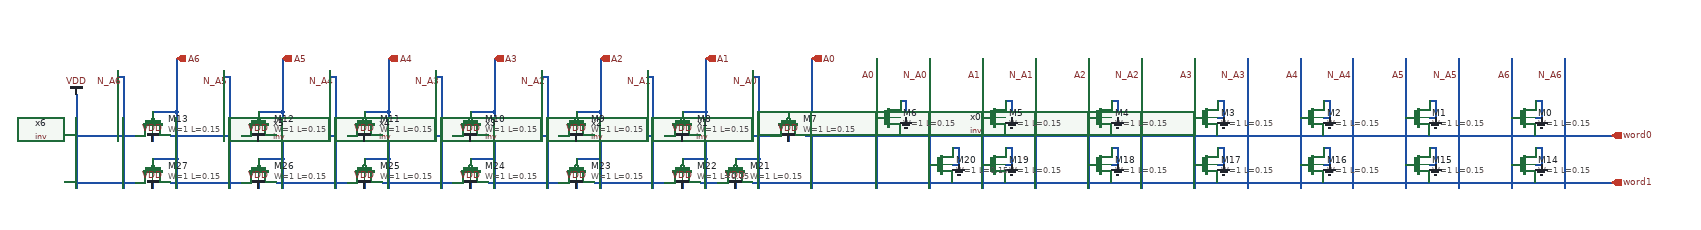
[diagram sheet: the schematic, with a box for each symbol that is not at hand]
v {xschem version=3.4.6 file_version=1.2}
G {}
K {}
V {}
S {}
E {}
N 1450 -60 1450 0 { }
N 1360 -60 1360 0 { }
N 1630 -60 1630 0 { }
N 1540 -60 1540 0 { }
N 1810 -60 1810 0 { }
N 1720 -60 1720 0 { }
N 1990 -60 1990 0 { }
N 1900 -60 1900 0 { }
N 2170 -60 2170 0 { }
N 2080 -60 2080 0 { }
N 2350 -60 2350 0 { }
N 2260 -60 2260 0 { }
N 2530 -60 2530 0 { }
N 2440 -60 2440 0 { }
N 1250 -60 1250 0 {lab=A0}
N 1150 -40 1150 -30 {lab=N_A0}
N 1150 -30 1160 -30 {lab=N_A0}
N 1160 -30 1160 0 {lab=N_A0}
N 1070 -60 1070 0 {lab=A1}
N 970 -40 970 -30 {lab=N_A1}
N 970 -30 980 -30 {lab=N_A1}
N 980 -30 980 0 {lab=N_A1}
N 890 -60 890 0 {lab=A2}
N 790 -40 790 -30 {lab=N_A2}
N 790 -30 800 -30 {lab=N_A2}
N 800 -30 800 0 {lab=N_A2}
N 710 -60 710 0 {lab=A3}
N 610 -40 610 -30 {lab=N_A3}
N 610 -30 620 -30 {lab=N_A3}
N 620 -30 620 0 {lab=N_A3}
N 530 -60 530 0 {lab=A4}
N 430 -40 430 -30 {lab=N_A4}
N 430 -30 440 -30 {lab=N_A4}
N 440 -30 440 0 {lab=N_A4}
N 350 -60 350 0 {lab=A5}
N 250 -40 250 -30 {lab=N_A5}
N 250 -30 260 -30 {lab=N_A5}
N 260 -30 260 0 {lab=N_A5}
N 170 -60 170 0 {lab=A6}
N 70 -40 70 -30 {lab=N_A6}
N 70 -30 80 -30 {lab=N_A6}
N 80 -30 80 0 {lab=N_A6}
N 2530 0 2530 80 {lab=N_A6}
N 2520 70 2610 70 {lab=word0}
N 2480 40 2490 40 {lab=GND}
N 2490 10 2490 40 {lab=GND}
N 2480 10 2490 10 {lab=GND}
N 2440 0 2440 40 {lab=A6}
N 2440 40 2440 80 {lab=A6}
N 2430 70 2480 70 {lab=word0}
N 2480 70 2520 70 {lab=word0}
N 2350 0 2350 80 {lab=N_A5}
N 2340 70 2430 70 {lab=word0}
N 2300 40 2310 40 {lab=GND}
N 2310 10 2310 40 {lab=GND}
N 2300 10 2310 10 {lab=GND}
N 2260 0 2260 40 {lab=A5}
N 2260 40 2260 80 {lab=A5}
N 2250 70 2300 70 {lab=word0}
N 2300 70 2340 70 {lab=word0}
N 2170 0 2170 80 {lab=N_A4}
N 2160 70 2250 70 {lab=word0}
N 2120 40 2130 40 {lab=GND}
N 2130 10 2130 40 {lab=GND}
N 2120 10 2130 10 {lab=GND}
N 2080 0 2080 40 {lab=A4}
N 2080 40 2080 80 {lab=A4}
N 2070 70 2120 70 {lab=word0}
N 2120 70 2160 70 {lab=word0}
N 1990 0 1990 80 {lab=N_A3}
N 1980 70 2070 70 {lab=word0}
N 1940 40 1950 40 {lab=GND}
N 1950 10 1950 40 {lab=GND}
N 1940 10 1950 10 {lab=GND}
N 1900 0 1900 40 {lab=A3}
N 1900 40 1900 80 {lab=A3}
N 1890 70 1940 70 {lab=word0}
N 1940 70 1980 70 {lab=word0}
N 1810 0 1810 80 {lab=N_A2}
N 1800 70 1890 70 {lab=word0}
N 1760 40 1770 40 {lab=GND}
N 1770 10 1770 40 {lab=GND}
N 1760 10 1770 10 {lab=GND}
N 1720 0 1720 40 {lab=A2}
N 1720 40 1720 80 {lab=A2}
N 1710 70 1760 70 {lab=word0}
N 1760 70 1800 70 {lab=word0}
N 1630 0 1630 80 {lab=N_A1}
N 1620 70 1710 70 {lab=word0}
N 1580 40 1590 40 {lab=GND}
N 1590 10 1590 40 {lab=GND}
N 1580 10 1590 10 {lab=GND}
N 1540 0 1540 40 {lab=A1}
N 1540 40 1540 80 {lab=A1}
N 1530 70 1580 70 {lab=word0}
N 1580 70 1620 70 {lab=word0}
N 1450 0 1450 80 {lab=N_A0}
N 1440 70 1530 70 {lab=word0}
N 1400 40 1410 40 {lab=GND}
N 1410 10 1410 40 {lab=GND}
N 1400 10 1410 10 {lab=GND}
N 1360 0 1360 40 {lab=A0}
N 1360 40 1360 80 {lab=A0}
N 1350 70 1400 70 {lab=word0}
N 1400 70 1440 70 {lab=word0}
N 1260 70 1350 70 { }
N 1210 30 1250 30 {lab=A7}
N 1210 70 1210 80 {lab=VDD}
N 1240 70 1260 70 {lab=word0}
N 1170 70 1180 70 {lab=#net015}
N 1250 0 1250 30 {lab=A7}
N 1250 30 1250 80 {lab=A7}
N 1160 0 1160 80 {lab=N_A8}
N 1080 70 1170 70 {lab=#net015}
N 1030 30 1070 30 {lab=A8}
N 1030 70 1030 80 {lab=VDD}
N 1060 70 1080 70 {lab=#net015}
N 990 70 1000 70 {lab=#net017}
N 1070 0 1070 30 {lab=A8}
N 1070 30 1070 80 {lab=A8}
N 980 0 980 80 {lab=N_A9}
N 900 70 990 70 {lab=#net017}
N 850 30 890 30 {lab=A9}
N 850 70 850 80 {lab=VDD}
N 880 70 900 70 {lab=#net017}
N 810 70 820 70 {lab=#net019}
N 890 0 890 30 {lab=A9}
N 890 30 890 80 {lab=A9}
N 800 0 800 80 {lab=N_A10}
N 720 70 810 70 {lab=#net019}
N 670 30 710 30 {lab=A10}
N 670 70 670 80 {lab=VDD}
N 700 70 720 70 {lab=#net019}
N 630 70 640 70 {lab=#net021}
N 710 0 710 30 {lab=A10}
N 710 30 710 80 {lab=A10}
N 620 0 620 80 {lab=N_A11}
N 540 70 630 70 {lab=#net021}
N 490 30 530 30 {lab=A11}
N 490 70 490 80 {lab=VDD}
N 520 70 540 70 {lab=#net021}
N 450 70 460 70 {lab=#net023}
N 530 0 530 30 {lab=A11}
N 530 30 530 80 {lab=A11}
N 440 0 440 80 {lab=N_A12}
N 360 70 450 70 {lab=#net023}
N 310 30 350 30 {lab=A12}
N 310 70 310 80 {lab=VDD}
N 340 70 360 70 {lab=#net023}
N 270 70 280 70 {lab=#net025}
N 350 0 350 30 {lab=A12}
N 350 30 350 80 {lab=A12}
N 260 0 260 80 {lab=N_A13}
N 180 70 270 70 {lab=#net025}
N 130 30 170 30 {lab=A13}
N 130 70 130 80 {lab=VDD}
N 160 70 180 70 {lab=#net025}
N 90 70 100 70 {lab=#net027}
N 170 0 170 30 {lab=A13}
N 170 30 170 80 {lab=A13}
N 80 0 80 80 {lab=N_A14}
N 0 70 90 70 {lab=#net027}
N 0 0 0 80 { }
N 2530 80 2530 160 {lab=N_A6}
N 2520 150 2610 150 {lab=word1}
N 2480 120 2490 120 {lab=GND}
N 2490 90 2490 120 {lab=GND}
N 2480 90 2490 90 {lab=GND}
N 2440 80 2440 120 {lab=A6}
N 2440 120 2440 160 {lab=A6}
N 2430 150 2480 150 {lab=word1}
N 2480 150 2520 150 {lab=word1}
N 2350 80 2350 160 {lab=N_A5}
N 2340 150 2430 150 {lab=word1}
N 2300 120 2310 120 {lab=GND}
N 2310 90 2310 120 {lab=GND}
N 2300 90 2310 90 {lab=GND}
N 2260 80 2260 120 {lab=A5}
N 2260 120 2260 160 {lab=A5}
N 2250 150 2300 150 {lab=word1}
N 2300 150 2340 150 {lab=word1}
N 2170 80 2170 160 {lab=N_A4}
N 2160 150 2250 150 {lab=word1}
N 2120 120 2130 120 {lab=GND}
N 2130 90 2130 120 {lab=GND}
N 2120 90 2130 90 {lab=GND}
N 2080 80 2080 120 {lab=A4}
N 2080 120 2080 160 {lab=A4}
N 2070 150 2120 150 {lab=word1}
N 2120 150 2160 150 {lab=word1}
N 1990 80 1990 160 {lab=N_A3}
N 1980 150 2070 150 {lab=word1}
N 1940 120 1950 120 {lab=GND}
N 1950 90 1950 120 {lab=GND}
N 1940 90 1950 90 {lab=GND}
N 1900 80 1900 120 {lab=A3}
N 1900 120 1900 160 {lab=A3}
N 1890 150 1940 150 {lab=word1}
N 1940 150 1980 150 {lab=word1}
N 1810 80 1810 160 {lab=N_A2}
N 1800 150 1890 150 {lab=word1}
N 1760 120 1770 120 {lab=GND}
N 1770 90 1770 120 {lab=GND}
N 1760 90 1770 90 {lab=GND}
N 1720 80 1720 120 {lab=A2}
N 1720 120 1720 160 {lab=A2}
N 1710 150 1760 150 {lab=word1}
N 1760 150 1800 150 {lab=word1}
N 1630 80 1630 160 {lab=N_A1}
N 1620 150 1710 150 {lab=word1}
N 1580 120 1590 120 {lab=GND}
N 1590 90 1590 120 {lab=GND}
N 1580 90 1590 90 {lab=GND}
N 1540 80 1540 120 {lab=A1}
N 1540 120 1540 160 {lab=A1}
N 1530 150 1580 150 {lab=word1}
N 1580 150 1620 150 {lab=word1}
N 1490 120 1500 120 {lab=GND}
N 1500 90 1500 120 {lab=GND}
N 1490 90 1500 90 {lab=GND}
N 1450 80 1450 120 {lab=N_A0}
N 1450 120 1450 160 {lab=N_A0}
N 1440 150 1490 150 {lab=word1}
N 1490 150 1530 150 {lab=word1}
N 1360 80 1360 160 {lab=A0}
N 1350 150 1440 150 {lab=word1}
N 1260 150 1350 150 { }
N 1250 80 1250 160 {lab=A7}
N 1170 150 1260 150 {lab=word1}
N 1120 110 1160 110 {lab=N_A8}
N 1120 150 1120 160 {lab=VDD}
N 1150 150 1170 150 {lab=word1}
N 1080 150 1090 150 {lab=#net115}
N 1160 80 1160 110 {lab=N_A8}
N 1160 110 1160 160 {lab=N_A8}
N 1030 110 1070 110 {lab=A8}
N 1030 150 1030 160 {lab=VDD}
N 1060 150 1080 150 {lab=#net115}
N 990 150 1000 150 {lab=#net117}
N 1070 80 1070 110 {lab=A8}
N 1070 110 1070 160 {lab=A8}
N 980 80 980 160 {lab=N_A9}
N 900 150 990 150 {lab=#net117}
N 850 110 890 110 {lab=A9}
N 850 150 850 160 {lab=VDD}
N 880 150 900 150 {lab=#net117}
N 810 150 820 150 {lab=#net119}
N 890 80 890 110 {lab=A9}
N 890 110 890 160 {lab=A9}
N 800 80 800 160 {lab=N_A10}
N 720 150 810 150 {lab=#net119}
N 670 110 710 110 {lab=A10}
N 670 150 670 160 {lab=VDD}
N 700 150 720 150 {lab=#net119}
N 630 150 640 150 {lab=#net121}
N 710 80 710 110 {lab=A10}
N 710 110 710 160 {lab=A10}
N 620 80 620 160 {lab=N_A11}
N 540 150 630 150 {lab=#net121}
N 490 110 530 110 {lab=A11}
N 490 150 490 160 {lab=VDD}
N 520 150 540 150 {lab=#net121}
N 450 150 460 150 {lab=#net123}
N 530 80 530 110 {lab=A11}
N 530 110 530 160 {lab=A11}
N 440 80 440 160 {lab=N_A12}
N 360 150 450 150 {lab=#net123}
N 310 110 350 110 {lab=A12}
N 310 150 310 160 {lab=VDD}
N 340 150 360 150 {lab=#net123}
N 270 150 280 150 {lab=#net125}
N 350 80 350 110 {lab=A12}
N 350 110 350 160 {lab=A12}
N 260 80 260 160 {lab=N_A13}
N 180 150 270 150 {lab=#net125}
N 130 110 170 110 {lab=A13}
N 130 150 130 160 {lab=VDD}
N 160 150 180 150 {lab=#net125}
N 90 150 100 150 {lab=#net127}
N 170 80 170 110 {lab=A13}
N 170 110 170 160 {lab=A13}
N 80 80 80 160 {lab=N_A14}
N 0 150 90 150 {lab=#net127}
N 0 80 0 160 { }
C {devices/vdd.sym} 0 0 0 0 {lab=VDD}
C {devices/lab_wire.sym} 1450 -30 0 0 {name=p0 lab=N_A0}
C {devices/lab_wire.sym} 1360 -30 0 0 {name=p1 lab=A0}
C {devices/lab_wire.sym} 1630 -30 0 0 {name=p2 lab=N_A1}
C {devices/lab_wire.sym} 1540 -30 0 0 {name=p3 lab=A1}
C {devices/lab_wire.sym} 1810 -30 0 0 {name=p4 lab=N_A2}
C {devices/lab_wire.sym} 1720 -30 0 0 {name=p5 lab=A2}
C {devices/lab_wire.sym} 1990 -30 0 0 {name=p6 lab=N_A3}
C {devices/lab_wire.sym} 1900 -30 0 0 {name=p7 lab=A3}
C {devices/lab_wire.sym} 2170 -30 0 0 {name=p8 lab=N_A4}
C {devices/lab_wire.sym} 2080 -30 0 0 {name=p9 lab=A4}
C {devices/lab_wire.sym} 2350 -30 0 0 {name=p10 lab=N_A5}
C {devices/lab_wire.sym} 2260 -30 0 0 {name=p11 lab=A5}
C {devices/lab_wire.sym} 2530 -30 0 0 {name=p12 lab=N_A6}
C {devices/lab_wire.sym} 2440 -30 0 0 {name=p13 lab=A6}
C {lab1/inv.sym} 1250 -90 2 0 {name=x0}
C {devices/ipin.sym} 1250 -60 3 1 {name=p14 lab=A0}
C {devices/lab_wire.sym} 1160 -20 0 0 {name=p15 sig_type=std_logic lab=N_A0}
C {lab1/inv.sym} 1070 -90 2 0 {name=x1}
C {devices/ipin.sym} 1070 -60 3 1 {name=p16 lab=A1}
C {devices/lab_wire.sym} 980 -20 0 0 {name=p17 sig_type=std_logic lab=N_A1}
C {lab1/inv.sym} 890 -90 2 0 {name=x2}
C {devices/ipin.sym} 890 -60 3 1 {name=p18 lab=A2}
C {devices/lab_wire.sym} 800 -20 0 0 {name=p19 sig_type=std_logic lab=N_A2}
C {lab1/inv.sym} 710 -90 2 0 {name=x3}
C {devices/ipin.sym} 710 -60 3 1 {name=p20 lab=A3}
C {devices/lab_wire.sym} 620 -20 0 0 {name=p21 sig_type=std_logic lab=N_A3}
C {lab1/inv.sym} 530 -90 2 0 {name=x4}
C {devices/ipin.sym} 530 -60 3 1 {name=p22 lab=A4}
C {devices/lab_wire.sym} 440 -20 0 0 {name=p23 sig_type=std_logic lab=N_A4}
C {lab1/inv.sym} 350 -90 2 0 {name=x5}
C {devices/ipin.sym} 350 -60 3 1 {name=p24 lab=A5}
C {devices/lab_wire.sym} 260 -20 0 0 {name=p25 sig_type=std_logic lab=N_A5}
C {lab1/inv.sym} 170 -90 2 0 {name=x6}
C {devices/ipin.sym} 170 -60 3 1 {name=p26 lab=A6}
C {devices/lab_wire.sym} 80 -20 0 0 {name=p27 sig_type=std_logic lab=N_A6}
C {devices/opin.sym} 2610 70 0 0 {name=p28 lab=word0}
C {sky130_fd_pr/nfet_01v8.sym} 2460 40 2 1 {name=M0
L=0.15
W=1
nf=1 
mult=1
ad="'int((nf+1)/2) * W/nf * 0.29'" 
pd="'2*int((nf+1)/2) * (W/nf + 0.29)'"
as="'int((nf+2)/2) * W/nf * 0.29'" 
ps="'2*int((nf+2)/2) * (W/nf + 0.29)'"
nrd="'0.29 / W'" nrs="'0.29 / W'"
sa=0 sb=0 sd=0
model=nfet_01v8
spiceprefix=X
}
C {devices/gnd.sym} 2490 40 3 0 {name=l0 lab=GND}
C {sky130_fd_pr/nfet_01v8.sym} 2280 40 2 1 {name=M1
L=0.15
W=1
nf=1 
mult=1
ad="'int((nf+1)/2) * W/nf * 0.29'" 
pd="'2*int((nf+1)/2) * (W/nf + 0.29)'"
as="'int((nf+2)/2) * W/nf * 0.29'" 
ps="'2*int((nf+2)/2) * (W/nf + 0.29)'"
nrd="'0.29 / W'" nrs="'0.29 / W'"
sa=0 sb=0 sd=0
model=nfet_01v8
spiceprefix=X
}
C {devices/gnd.sym} 2310 40 3 0 {name=l1 lab=GND}
C {sky130_fd_pr/nfet_01v8.sym} 2100 40 2 1 {name=M2
L=0.15
W=1
nf=1 
mult=1
ad="'int((nf+1)/2) * W/nf * 0.29'" 
pd="'2*int((nf+1)/2) * (W/nf + 0.29)'"
as="'int((nf+2)/2) * W/nf * 0.29'" 
ps="'2*int((nf+2)/2) * (W/nf + 0.29)'"
nrd="'0.29 / W'" nrs="'0.29 / W'"
sa=0 sb=0 sd=0
model=nfet_01v8
spiceprefix=X
}
C {devices/gnd.sym} 2130 40 3 0 {name=l2 lab=GND}
C {sky130_fd_pr/nfet_01v8.sym} 1920 40 2 1 {name=M3
L=0.15
W=1
nf=1 
mult=1
ad="'int((nf+1)/2) * W/nf * 0.29'" 
pd="'2*int((nf+1)/2) * (W/nf + 0.29)'"
as="'int((nf+2)/2) * W/nf * 0.29'" 
ps="'2*int((nf+2)/2) * (W/nf + 0.29)'"
nrd="'0.29 / W'" nrs="'0.29 / W'"
sa=0 sb=0 sd=0
model=nfet_01v8
spiceprefix=X
}
C {devices/gnd.sym} 1950 40 3 0 {name=l3 lab=GND}
C {sky130_fd_pr/nfet_01v8.sym} 1740 40 2 1 {name=M4
L=0.15
W=1
nf=1 
mult=1
ad="'int((nf+1)/2) * W/nf * 0.29'" 
pd="'2*int((nf+1)/2) * (W/nf + 0.29)'"
as="'int((nf+2)/2) * W/nf * 0.29'" 
ps="'2*int((nf+2)/2) * (W/nf + 0.29)'"
nrd="'0.29 / W'" nrs="'0.29 / W'"
sa=0 sb=0 sd=0
model=nfet_01v8
spiceprefix=X
}
C {devices/gnd.sym} 1770 40 3 0 {name=l4 lab=GND}
C {sky130_fd_pr/nfet_01v8.sym} 1560 40 2 1 {name=M5
L=0.15
W=1
nf=1 
mult=1
ad="'int((nf+1)/2) * W/nf * 0.29'" 
pd="'2*int((nf+1)/2) * (W/nf + 0.29)'"
as="'int((nf+2)/2) * W/nf * 0.29'" 
ps="'2*int((nf+2)/2) * (W/nf + 0.29)'"
nrd="'0.29 / W'" nrs="'0.29 / W'"
sa=0 sb=0 sd=0
model=nfet_01v8
spiceprefix=X
}
C {devices/gnd.sym} 1590 40 3 0 {name=l5 lab=GND}
C {sky130_fd_pr/nfet_01v8.sym} 1380 40 2 1 {name=M6
L=0.15
W=1
nf=1 
mult=1
ad="'int((nf+1)/2) * W/nf * 0.29'" 
pd="'2*int((nf+1)/2) * (W/nf + 0.29)'"
as="'int((nf+2)/2) * W/nf * 0.29'" 
ps="'2*int((nf+2)/2) * (W/nf + 0.29)'"
nrd="'0.29 / W'" nrs="'0.29 / W'"
sa=0 sb=0 sd=0
model=nfet_01v8
spiceprefix=X
}
C {devices/gnd.sym} 1410 40 3 0 {name=l6 lab=GND}
C {sky130_fd_pr/pfet_01v8.sym} 1210 50 3 1 {name=M7
L=0.15
W=1
nf=1
mult=1
ad="'int((nf+1)/2) * W/nf * 0.29'" 
pd="'2*int((nf+1)/2) * (W/nf + 0.29)'"
as="'int((nf+2)/2) * W/nf * 0.29'" 
ps="'2*int((nf+2)/2) * (W/nf + 0.29)'"
nrd="'0.29 / W'" nrs="'0.29 / W'"
sa=0 sb=0 sd=0
model=pfet_01v8
spiceprefix=X
}
C {devices/vdd.sym} 1210 80 3 0 {name=l7 lab=VDD}
C {sky130_fd_pr/pfet_01v8.sym} 1030 50 3 1 {name=M8
L=0.15
W=1
nf=1
mult=1
ad="'int((nf+1)/2) * W/nf * 0.29'" 
pd="'2*int((nf+1)/2) * (W/nf + 0.29)'"
as="'int((nf+2)/2) * W/nf * 0.29'" 
ps="'2*int((nf+2)/2) * (W/nf + 0.29)'"
nrd="'0.29 / W'" nrs="'0.29 / W'"
sa=0 sb=0 sd=0
model=pfet_01v8
spiceprefix=X
}
C {devices/vdd.sym} 1030 80 3 0 {name=l8 lab=VDD}
C {sky130_fd_pr/pfet_01v8.sym} 850 50 3 1 {name=M9
L=0.15
W=1
nf=1
mult=1
ad="'int((nf+1)/2) * W/nf * 0.29'" 
pd="'2*int((nf+1)/2) * (W/nf + 0.29)'"
as="'int((nf+2)/2) * W/nf * 0.29'" 
ps="'2*int((nf+2)/2) * (W/nf + 0.29)'"
nrd="'0.29 / W'" nrs="'0.29 / W'"
sa=0 sb=0 sd=0
model=pfet_01v8
spiceprefix=X
}
C {devices/vdd.sym} 850 80 3 0 {name=l9 lab=VDD}
C {sky130_fd_pr/pfet_01v8.sym} 670 50 3 1 {name=M10
L=0.15
W=1
nf=1
mult=1
ad="'int((nf+1)/2) * W/nf * 0.29'" 
pd="'2*int((nf+1)/2) * (W/nf + 0.29)'"
as="'int((nf+2)/2) * W/nf * 0.29'" 
ps="'2*int((nf+2)/2) * (W/nf + 0.29)'"
nrd="'0.29 / W'" nrs="'0.29 / W'"
sa=0 sb=0 sd=0
model=pfet_01v8
spiceprefix=X
}
C {devices/vdd.sym} 670 80 3 0 {name=l10 lab=VDD}
C {sky130_fd_pr/pfet_01v8.sym} 490 50 3 1 {name=M11
L=0.15
W=1
nf=1
mult=1
ad="'int((nf+1)/2) * W/nf * 0.29'" 
pd="'2*int((nf+1)/2) * (W/nf + 0.29)'"
as="'int((nf+2)/2) * W/nf * 0.29'" 
ps="'2*int((nf+2)/2) * (W/nf + 0.29)'"
nrd="'0.29 / W'" nrs="'0.29 / W'"
sa=0 sb=0 sd=0
model=pfet_01v8
spiceprefix=X
}
C {devices/vdd.sym} 490 80 3 0 {name=l11 lab=VDD}
C {sky130_fd_pr/pfet_01v8.sym} 310 50 3 1 {name=M12
L=0.15
W=1
nf=1
mult=1
ad="'int((nf+1)/2) * W/nf * 0.29'" 
pd="'2*int((nf+1)/2) * (W/nf + 0.29)'"
as="'int((nf+2)/2) * W/nf * 0.29'" 
ps="'2*int((nf+2)/2) * (W/nf + 0.29)'"
nrd="'0.29 / W'" nrs="'0.29 / W'"
sa=0 sb=0 sd=0
model=pfet_01v8
spiceprefix=X
}
C {devices/vdd.sym} 310 80 3 0 {name=l12 lab=VDD}
C {sky130_fd_pr/pfet_01v8.sym} 130 50 3 1 {name=M13
L=0.15
W=1
nf=1
mult=1
ad="'int((nf+1)/2) * W/nf * 0.29'" 
pd="'2*int((nf+1)/2) * (W/nf + 0.29)'"
as="'int((nf+2)/2) * W/nf * 0.29'" 
ps="'2*int((nf+2)/2) * (W/nf + 0.29)'"
nrd="'0.29 / W'" nrs="'0.29 / W'"
sa=0 sb=0 sd=0
model=pfet_01v8
spiceprefix=X
}
C {devices/vdd.sym} 130 80 3 0 {name=l13 lab=VDD}
C {devices/opin.sym} 2610 150 0 0 {name=p29 lab=word1}
C {sky130_fd_pr/nfet_01v8.sym} 2460 120 2 1 {name=M14
L=0.15
W=1
nf=1 
mult=1
ad="'int((nf+1)/2) * W/nf * 0.29'" 
pd="'2*int((nf+1)/2) * (W/nf + 0.29)'"
as="'int((nf+2)/2) * W/nf * 0.29'" 
ps="'2*int((nf+2)/2) * (W/nf + 0.29)'"
nrd="'0.29 / W'" nrs="'0.29 / W'"
sa=0 sb=0 sd=0
model=nfet_01v8
spiceprefix=X
}
C {devices/gnd.sym} 2490 120 3 0 {name=l14 lab=GND}
C {sky130_fd_pr/nfet_01v8.sym} 2280 120 2 1 {name=M15
L=0.15
W=1
nf=1 
mult=1
ad="'int((nf+1)/2) * W/nf * 0.29'" 
pd="'2*int((nf+1)/2) * (W/nf + 0.29)'"
as="'int((nf+2)/2) * W/nf * 0.29'" 
ps="'2*int((nf+2)/2) * (W/nf + 0.29)'"
nrd="'0.29 / W'" nrs="'0.29 / W'"
sa=0 sb=0 sd=0
model=nfet_01v8
spiceprefix=X
}
C {devices/gnd.sym} 2310 120 3 0 {name=l15 lab=GND}
C {sky130_fd_pr/nfet_01v8.sym} 2100 120 2 1 {name=M16
L=0.15
W=1
nf=1 
mult=1
ad="'int((nf+1)/2) * W/nf * 0.29'" 
pd="'2*int((nf+1)/2) * (W/nf + 0.29)'"
as="'int((nf+2)/2) * W/nf * 0.29'" 
ps="'2*int((nf+2)/2) * (W/nf + 0.29)'"
nrd="'0.29 / W'" nrs="'0.29 / W'"
sa=0 sb=0 sd=0
model=nfet_01v8
spiceprefix=X
}
C {devices/gnd.sym} 2130 120 3 0 {name=l16 lab=GND}
C {sky130_fd_pr/nfet_01v8.sym} 1920 120 2 1 {name=M17
L=0.15
W=1
nf=1 
mult=1
ad="'int((nf+1)/2) * W/nf * 0.29'" 
pd="'2*int((nf+1)/2) * (W/nf + 0.29)'"
as="'int((nf+2)/2) * W/nf * 0.29'" 
ps="'2*int((nf+2)/2) * (W/nf + 0.29)'"
nrd="'0.29 / W'" nrs="'0.29 / W'"
sa=0 sb=0 sd=0
model=nfet_01v8
spiceprefix=X
}
C {devices/gnd.sym} 1950 120 3 0 {name=l17 lab=GND}
C {sky130_fd_pr/nfet_01v8.sym} 1740 120 2 1 {name=M18
L=0.15
W=1
nf=1 
mult=1
ad="'int((nf+1)/2) * W/nf * 0.29'" 
pd="'2*int((nf+1)/2) * (W/nf + 0.29)'"
as="'int((nf+2)/2) * W/nf * 0.29'" 
ps="'2*int((nf+2)/2) * (W/nf + 0.29)'"
nrd="'0.29 / W'" nrs="'0.29 / W'"
sa=0 sb=0 sd=0
model=nfet_01v8
spiceprefix=X
}
C {devices/gnd.sym} 1770 120 3 0 {name=l18 lab=GND}
C {sky130_fd_pr/nfet_01v8.sym} 1560 120 2 1 {name=M19
L=0.15
W=1
nf=1 
mult=1
ad="'int((nf+1)/2) * W/nf * 0.29'" 
pd="'2*int((nf+1)/2) * (W/nf + 0.29)'"
as="'int((nf+2)/2) * W/nf * 0.29'" 
ps="'2*int((nf+2)/2) * (W/nf + 0.29)'"
nrd="'0.29 / W'" nrs="'0.29 / W'"
sa=0 sb=0 sd=0
model=nfet_01v8
spiceprefix=X
}
C {devices/gnd.sym} 1590 120 3 0 {name=l19 lab=GND}
C {sky130_fd_pr/nfet_01v8.sym} 1470 120 2 1 {name=M20
L=0.15
W=1
nf=1 
mult=1
ad="'int((nf+1)/2) * W/nf * 0.29'" 
pd="'2*int((nf+1)/2) * (W/nf + 0.29)'"
as="'int((nf+2)/2) * W/nf * 0.29'" 
ps="'2*int((nf+2)/2) * (W/nf + 0.29)'"
nrd="'0.29 / W'" nrs="'0.29 / W'"
sa=0 sb=0 sd=0
model=nfet_01v8
spiceprefix=X
}
C {devices/gnd.sym} 1500 120 3 0 {name=l20 lab=GND}
C {sky130_fd_pr/pfet_01v8.sym} 1120 130 3 1 {name=M21
L=0.15
W=1
nf=1
mult=1
ad="'int((nf+1)/2) * W/nf * 0.29'" 
pd="'2*int((nf+1)/2) * (W/nf + 0.29)'"
as="'int((nf+2)/2) * W/nf * 0.29'" 
ps="'2*int((nf+2)/2) * (W/nf + 0.29)'"
nrd="'0.29 / W'" nrs="'0.29 / W'"
sa=0 sb=0 sd=0
model=pfet_01v8
spiceprefix=X
}
C {devices/vdd.sym} 1120 160 3 0 {name=l21 lab=VDD}
C {sky130_fd_pr/pfet_01v8.sym} 1030 130 3 1 {name=M22
L=0.15
W=1
nf=1
mult=1
ad="'int((nf+1)/2) * W/nf * 0.29'" 
pd="'2*int((nf+1)/2) * (W/nf + 0.29)'"
as="'int((nf+2)/2) * W/nf * 0.29'" 
ps="'2*int((nf+2)/2) * (W/nf + 0.29)'"
nrd="'0.29 / W'" nrs="'0.29 / W'"
sa=0 sb=0 sd=0
model=pfet_01v8
spiceprefix=X
}
C {devices/vdd.sym} 1030 160 3 0 {name=l22 lab=VDD}
C {sky130_fd_pr/pfet_01v8.sym} 850 130 3 1 {name=M23
L=0.15
W=1
nf=1
mult=1
ad="'int((nf+1)/2) * W/nf * 0.29'" 
pd="'2*int((nf+1)/2) * (W/nf + 0.29)'"
as="'int((nf+2)/2) * W/nf * 0.29'" 
ps="'2*int((nf+2)/2) * (W/nf + 0.29)'"
nrd="'0.29 / W'" nrs="'0.29 / W'"
sa=0 sb=0 sd=0
model=pfet_01v8
spiceprefix=X
}
C {devices/vdd.sym} 850 160 3 0 {name=l23 lab=VDD}
C {sky130_fd_pr/pfet_01v8.sym} 670 130 3 1 {name=M24
L=0.15
W=1
nf=1
mult=1
ad="'int((nf+1)/2) * W/nf * 0.29'" 
pd="'2*int((nf+1)/2) * (W/nf + 0.29)'"
as="'int((nf+2)/2) * W/nf * 0.29'" 
ps="'2*int((nf+2)/2) * (W/nf + 0.29)'"
nrd="'0.29 / W'" nrs="'0.29 / W'"
sa=0 sb=0 sd=0
model=pfet_01v8
spiceprefix=X
}
C {devices/vdd.sym} 670 160 3 0 {name=l24 lab=VDD}
C {sky130_fd_pr/pfet_01v8.sym} 490 130 3 1 {name=M25
L=0.15
W=1
nf=1
mult=1
ad="'int((nf+1)/2) * W/nf * 0.29'" 
pd="'2*int((nf+1)/2) * (W/nf + 0.29)'"
as="'int((nf+2)/2) * W/nf * 0.29'" 
ps="'2*int((nf+2)/2) * (W/nf + 0.29)'"
nrd="'0.29 / W'" nrs="'0.29 / W'"
sa=0 sb=0 sd=0
model=pfet_01v8
spiceprefix=X
}
C {devices/vdd.sym} 490 160 3 0 {name=l25 lab=VDD}
C {sky130_fd_pr/pfet_01v8.sym} 310 130 3 1 {name=M26
L=0.15
W=1
nf=1
mult=1
ad="'int((nf+1)/2) * W/nf * 0.29'" 
pd="'2*int((nf+1)/2) * (W/nf + 0.29)'"
as="'int((nf+2)/2) * W/nf * 0.29'" 
ps="'2*int((nf+2)/2) * (W/nf + 0.29)'"
nrd="'0.29 / W'" nrs="'0.29 / W'"
sa=0 sb=0 sd=0
model=pfet_01v8
spiceprefix=X
}
C {devices/vdd.sym} 310 160 3 0 {name=l26 lab=VDD}
C {sky130_fd_pr/pfet_01v8.sym} 130 130 3 1 {name=M27
L=0.15
W=1
nf=1
mult=1
ad="'int((nf+1)/2) * W/nf * 0.29'" 
pd="'2*int((nf+1)/2) * (W/nf + 0.29)'"
as="'int((nf+2)/2) * W/nf * 0.29'" 
ps="'2*int((nf+2)/2) * (W/nf + 0.29)'"
nrd="'0.29 / W'" nrs="'0.29 / W'"
sa=0 sb=0 sd=0
model=pfet_01v8
spiceprefix=X
}
C {devices/vdd.sym} 130 160 3 0 {name=l27 lab=VDD}
